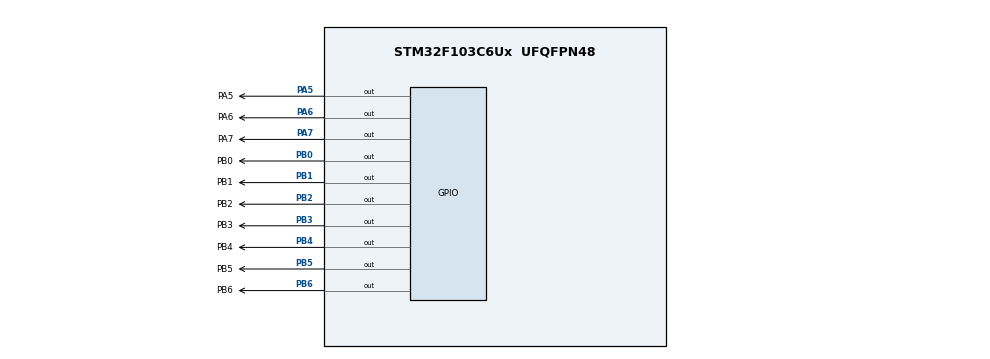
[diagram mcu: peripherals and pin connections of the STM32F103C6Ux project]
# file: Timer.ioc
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Mcu.Family=STM32F1
Mcu.Name=STM32F103C6Ux
Mcu.Package=UFQFPN48
NVIC.PriorityGroup=NVIC_PRIORITYGROUP_4
NVIC.TIM2_IRQn=true\:0\:0\:false\:false\:true\:true\:true
PA5.GPIO_Label=PA5
PA5.Signal=GPIO_Output
PA6.GPIO_Label=PA6
PA6.Signal=GPIO_Output
PA7.GPIO_Label=PA7
PA7.Signal=GPIO_Output
PB0.GPIO_Label=PB0
PB0.Signal=GPIO_Output
PB1.GPIO_Label=PB1
PB1.Signal=GPIO_Output
PB2.GPIO_Label=PB2
PB2.Signal=GPIO_Output
PB3.GPIO_Label=PB3
PB3.Signal=GPIO_Output
PB4.GPIO_Label=PB4
PB4.Signal=GPIO_Output
PB5.GPIO_Label=PB5
PB5.Signal=GPIO_Output
PB6.GPIO_Label=PB6
PB6.Signal=GPIO_Output
ProjectManager.HeapSize=0x200
ProjectManager.StackSize=0x400
ProjectManager.TargetToolchain=STM32CubeIDE
RCC.APB1Freq_Value=8000000
RCC.APB2Freq_Value=8000000
TIM2.Period=9
TIM2.Prescaler=7999
VP_SYS_VS_ND.Mode=No_Debug
VP_TIM2_VS_ClockSourceINT.Mode=Internal
board=custom

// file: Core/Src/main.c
/* USER CODE BEGIN Header */
/**
  ******************************************************************************
  * @file           : main.c
  * @brief          : Main program body
  ******************************************************************************
  * @attention
  *
  * <h2><center>&copy; Copyright (c) 2022 STMicroelectronics.
  * All rights reserved.</center></h2>
  *
  * This software component is licensed by ST under BSD 3-Clause license,
  * the "License"; You may not use this file except in compliance with the
  * License. You may obtain a copy of the License at:
  *                        opensource.org/licenses/BSD-3-Clause
  *
  ******************************************************************************
  */
/* USER CODE END Header */
#ifndef __SOFTWARE_TIMER_
#define __SOFTWARE_TIMER_

extern int timer1_flag;

void setTimer(int duration);
void timerRun();

void display7SEG(int num)
{
	//0
	    if(num == 0){
	    HAL_GPIO_WritePin(PB0_GPIO_Port, PB0_Pin , 0);
	    HAL_GPIO_WritePin(PB1_GPIO_Port, PB1_Pin , 0);
	    HAL_GPIO_WritePin(PB2_GPIO_Port, PB2_Pin , 0);
	    HAL_GPIO_WritePin(PB3_GPIO_Port, PB3_Pin , 0);
	    HAL_GPIO_WritePin(PB4_GPIO_Port, PB4_Pin , 0);
	    HAL_GPIO_WritePin(PB5_GPIO_Port, PB5_Pin , 0);
	    HAL_GPIO_WritePin(PB6_GPIO_Port, PB6_Pin , 1);
	    }
	    //1
	    if(num==1){
	    HAL_GPIO_WritePin(PB0_GPIO_Port, PB0_Pin , GPIO_PIN_SET);
	    HAL_GPIO_WritePin(PB1_GPIO_Port, PB2_Pin , GPIO_PIN_RESET);
	    HAL_GPIO_WritePin(PB2_GPIO_Port, PB3_Pin , GPIO_PIN_RESET);
	    HAL_GPIO_WritePin(PB3_GPIO_Port, PB4_Pin , GPIO_PIN_SET);
	    HAL_GPIO_WritePin(PB4_GPIO_Port, PB5_Pin , GPIO_PIN_SET);
	    HAL_GPIO_WritePin(PB5_GPIO_Port, PB6_Pin , GPIO_PIN_SET);
	    HAL_GPIO_WritePin(PB6_GPIO_Port, PB7_Pin , GPIO_PIN_SET);
	    }
	    //2
	    if(num==2){
	    HAL_GPIO_WritePin(PB0_GPIO_Port, PB0_Pin , GPIO_PIN_RESET);//
	    HAL_GPIO_WritePin(PB1_GPIO_Port, PB1_Pin , GPIO_PIN_RESET);
	    HAL_GPIO_WritePin(PB2_GPIO_Port, PB2_Pin , GPIO_PIN_SET);
	    HAL_GPIO_WritePin(PB3_GPIO_Port, PB3_Pin , GPIO_PIN_RESET);
	    HAL_GPIO_WritePin(PB4_GPIO_Port, PB4_Pin , GPIO_PIN_RESET);
	    HAL_GPIO_WritePin(PB5_GPIO_Port, PB5_Pin , GPIO_PIN_SET);
	    HAL_GPIO_WritePin(PB6_GPIO_Port, PB6_Pin , GPIO_PIN_RESET);
	    }
	    //3
	    if(num==3){
	    HAL_GPIO_WritePin(PB0_GPIO_Port, PB0_Pin , GPIO_PIN_RESET);
	    HAL_GPIO_WritePin(PB1_GPIO_Port, PB1_Pin , GPIO_PIN_RESET);
	    HAL_GPIO_WritePin(PB2_GPIO_Port, PB2_Pin , GPIO_PIN_RESET);
	    HAL_GPIO_WritePin(PB3_GPIO_Port, PB3_Pin , GPIO_PIN_RESET);
	    HAL_GPIO_WritePin(PB4_GPIO_Port, PB4_Pin , GPIO_PIN_SET);
	    HAL_GPIO_WritePin(PB5_GPIO_Port, PB5_Pin , GPIO_PIN_SET);
	    HAL_GPIO_WritePin(PB6_GPIO_Port, PB6_Pin , GPIO_PIN_RESET);
	   }
	    //4
	    if(num==4){
	    HAL_GPIO_WritePin(PB0_GPIO_Port, PB0_Pin , GPIO_PIN_SET);
	    HAL_GPIO_WritePin(PB1_GPIO_Port, PB1_Pin , GPIO_PIN_RESET);
	    HAL_GPIO_WritePin(PB2_GPIO_Port, PB2_Pin , GPIO_PIN_RESET);
	    HAL_GPIO_WritePin(PB3_GPIO_Port, PB3_Pin , GPIO_PIN_SET);
	    HAL_GPIO_WritePin(PB4_GPIO_Port, PB4_Pin , GPIO_PIN_SET);
	    HAL_GPIO_WritePin(PB5_GPIO_Port, PB5_Pin , GPIO_PIN_RESET);
	    HAL_GPIO_WritePin(PB6_GPIO_Port, PB6_Pin , GPIO_PIN_RESET);
	    }
	   //5
	    if(num==5){
	    HAL_GPIO_WritePin(PB0_GPIO_Port, PB0_Pin , GPIO_PIN_RESET);
	    HAL_GPIO_WritePin(PB1_GPIO_Port, PB1_Pin , GPIO_PIN_SET);
	    HAL_GPIO_WritePin(PB2_GPIO_Port, PB2_Pin , GPIO_PIN_RESET);
	    HAL_GPIO_WritePin(PB3_GPIO_Port, PB3_Pin , GPIO_PIN_RESET);
	    HAL_GPIO_WritePin(PB4_GPIO_Port, PB4_Pin , GPIO_PIN_SET);
	    HAL_GPIO_WritePin(PB5_GPIO_Port, PB5_Pin , GPIO_PIN_RESET);
	    HAL_GPIO_WritePin(PB6_GPIO_Port, PB6_Pin , GPIO_PIN_RESET);
	    }
	    //6
	    if(num==6){
	    HAL_GPIO_WritePin(PB0_GPIO_Port, PB0_Pin , GPIO_PIN_RESET);
	    HAL_GPIO_WritePin(PB1_GPIO_Port, PB1_Pin , GPIO_PIN_SET);
	    HAL_GPIO_WritePin(PB2_GPIO_Port, PB2_Pin , GPIO_PIN_RESET);
	    HAL_GPIO_WritePin(PB3_GPIO_Port, PB3_Pin , GPIO_PIN_RESET);
	    HAL_GPIO_WritePin(PB4_GPIO_Port, PB4_Pin , GPIO_PIN_RESET);
	    HAL_GPIO_WritePin(PB5_GPIO_Port, PB5_Pin , GPIO_PIN_RESET);
	    HAL_GPIO_WritePin(PB6_GPIO_Port, PB6_Pin , GPIO_PIN_RESET);
	    }
	    //7
	    if(num==7){
	    HAL_GPIO_WritePin(PB1_GPIO_Port, PB1_Pin , GPIO_PIN_RESET);
	    HAL_GPIO_WritePin(PB2_GPIO_Port, PB2_Pin , GPIO_PIN_RESET);
	    HAL_GPIO_WritePin(PB3_GPIO_Port, PB3_Pin , GPIO_PIN_RESET);
	    HAL_GPIO_WritePin(PB4_GPIO_Port, PB4_Pin , GPIO_PIN_SET);
	    HAL_GPIO_WritePin(PB5_GPIO_Port, PB5_Pin , GPIO_PIN_SET);
	    HAL_GPIO_WritePin(PB6_GPIO_Port, PB6_Pin , GPIO_PIN_SET);
	    HAL_GPIO_WritePin(PB7_GPIO_Port, PB7_Pin , GPIO_PIN_SET);
	    }
	    //8
	    if(num==8){
	    HAL_GPIO_WritePin(PB1_GPIO_Port, PB1_Pin , GPIO_PIN_RESET);
	    HAL_GPIO_WritePin(PB2_GPIO_Port, PB2_Pin , GPIO_PIN_RESET);
	    HAL_GPIO_WritePin(PB3_GPIO_Port, PB3_Pin , GPIO_PIN_RESET);
	    HAL_GPIO_WritePin(PB4_GPIO_Port, PB4_Pin , GPIO_PIN_RESET);
	    HAL_GPIO_WritePin(PB5_GPIO_Port, PB5_Pin , GPIO_PIN_RESET);
	    HAL_GPIO_WritePin(PB6_GPIO_Port, PB6_Pin , GPIO_PIN_RESET);
	    HAL_GPIO_WritePin(PB7_GPIO_Port, PB7_Pin , GPIO_PIN_RESET);
	   }
	    //9
	    if(num==9){
	    HAL_GPIO_WritePin(PB1_GPIO_Port, PB1_Pin , GPIO_PIN_RESET);
	    HAL_GPIO_WritePin(PB2_GPIO_Port, PB2_Pin , GPIO_PIN_RESET);
	    HAL_GPIO_WritePin(PB3_GPIO_Port, PB3_Pin , GPIO_PIN_RESET);
	    HAL_GPIO_WritePin(PB4_GPIO_Port, PB4_Pin , GPIO_PIN_RESET);
	    HAL_GPIO_WritePin(PB5_GPIO_Port, PB5_Pin , GPIO_PIN_SET);
	    HAL_GPIO_WritePin(PB6_GPIO_Port, PB6_Pin , GPIO_PIN_RESET);
	    HAL_GPIO_WritePin(PB7_GPIO_Port, PB7_Pin , GPIO_PIN_RESET);

	    }
}

#endif
#include "main.h"

int timer1_counter = 0;
int timer1_flag = 0;

void setTimer(int duration){
	timer1_counter = duration;
	timer1_flag = 0;
}
void timerRun(){
	if(timer1_counter > 0){
		timer1_counter--;
		if(timer1_counter == 0){
			timer1_flag = 1;
		}
	}
}

/* USER CODE BEGIN Includes */
#include "software_timer.h"
/* USER CODE END Includes */

TIM_HandleTypeDef htim2;

void SystemClock_Config(void);
static void MX_GPIO_Init(void);
static void MX_TIM2_Init(void);

int main(void)
{

  HAL_Init();

  SystemClock_Config();

  MX_GPIO_Init();
  MX_TIM2_Init();

  HAL_TIM_Base_Start_IT (& htim2 ) ;

  while (1)
  {

  }

}

void SystemClock_Config(void)
{
  RCC_OscInitTypeDef RCC_OscInitStruct = {0};
  RCC_ClkInitTypeDef RCC_ClkInitStruct = {0};

  /** Initializes the RCC Oscillators according to the specified parameters
  * in the RCC_OscInitTypeDef structure.
  */
  RCC_OscInitStruct.OscillatorType = RCC_OSCILLATORTYPE_HSI;
  RCC_OscInitStruct.HSIState = RCC_HSI_ON;
  RCC_OscInitStruct.HSICalibrationValue = RCC_HSICALIBRATION_DEFAULT;
  RCC_OscInitStruct.PLL.PLLState = RCC_PLL_NONE;
  if (HAL_RCC_OscConfig(&RCC_OscInitStruct) != HAL_OK)
  {
    Error_Handler();
  }
  /** Initializes the CPU, AHB and APB buses clocks
  */
  RCC_ClkInitStruct.ClockType = RCC_CLOCKTYPE_HCLK|RCC_CLOCKTYPE_SYSCLK
                              |RCC_CLOCKTYPE_PCLK1|RCC_CLOCKTYPE_PCLK2;
  RCC_ClkInitStruct.SYSCLKSource = RCC_SYSCLKSOURCE_HSI;
  RCC_ClkInitStruct.AHBCLKDivider = RCC_SYSCLK_DIV1;
  RCC_ClkInitStruct.APB1CLKDivider = RCC_HCLK_DIV1;
  RCC_ClkInitStruct.APB2CLKDivider = RCC_HCLK_DIV1;

  if (HAL_RCC_ClockConfig(&RCC_ClkInitStruct, FLASH_LATENCY_0) != HAL_OK)
  {
    Error_Handler();
  }
}

static void MX_TIM2_Init(void)
{

  TIM_ClockConfigTypeDef sClockSourceConfig = {0};
  TIM_MasterConfigTypeDef sMasterConfig = {0};

  htim2.Instance = TIM2;
  htim2.Init.Prescaler = 7999;
  htim2.Init.CounterMode = TIM_COUNTERMODE_UP;
  htim2.Init.Period = 9;
  htim2.Init.ClockDivision = TIM_CLOCKDIVISION_DIV1;
  htim2.Init.AutoReloadPreload = TIM_AUTORELOAD_PRELOAD_DISABLE;
  if (HAL_TIM_Base_Init(&htim2) != HAL_OK)
  {
    Error_Handler();
  }
  sClockSourceConfig.ClockSource = TIM_CLOCKSOURCE_INTERNAL;
  if (HAL_TIM_ConfigClockSource(&htim2, &sClockSourceConfig) != HAL_OK)
  {
    Error_Handler();
  }
  sMasterConfig.MasterOutputTrigger = TIM_TRGO_RESET;
  sMasterConfig.MasterSlaveMode = TIM_MASTERSLAVEMODE_DISABLE;
  if (HAL_TIMEx_MasterConfigSynchronization(&htim2, &sMasterConfig) != HAL_OK)
  {
    Error_Handler();
  }

}

static void MX_GPIO_Init(void)
{
  GPIO_InitTypeDef GPIO_InitStruct = {0};

  /* GPIO Ports Clock Enable */
  __HAL_RCC_GPIOA_CLK_ENABLE();

  /*Configure GPIO pin Output Level */

  /*Configure GPIO pins : LED_RED_Pin LED_GREEN_Pin */
  GPIO_InitStruct.Pin = LED_RED_Pin|LED_GREEN_Pin;
  GPIO_InitStruct.Mode = GPIO_MODE_OUTPUT_PP;
  GPIO_InitStruct.Pull = GPIO_NOPULL;
  GPIO_InitStruct.Speed = GPIO_SPEED_FREQ_LOW;
  HAL_GPIO_Init(GPIOA, &GPIO_InitStruct);

}

/* USER CODE BEGIN 4 */

int counter = 100;
int firstDisplay=1, secondDisplay =2 ;
int state=0;
void HAL_TIM_PeriodElapsedCallback ( TIM_HandleTypeDef * htim )
{
timerRun();
counter--;
if(counter==50){
	HAL_GPIO_WritePin(GPIOA, PA6_Pin|PA6_Pin, 1);
	display7SEG(firstDisplay);
	HAL_GPIO_WritePin(GPIOA, PA6_Pin|PA6_Pin, 0);

}
if(counter==0){
	HAL_GPIO_WritePin(GPIOA, PA7_Pin|PA7_Pin, 1);
	display7SEG(secondDisplay);
	HAL_GPIO_WritePin(GPIOA, PA6_Pin|PA6_Pin, 0);
	counter = 100;
}
}

/* USER CODE END 4 */

void Error_Handler(void)
{
  __disable_irq();
  while (1)
  {
  }
}

/************************ (C) COPYRIGHT STMicroelectronics *****END OF FILE****/
